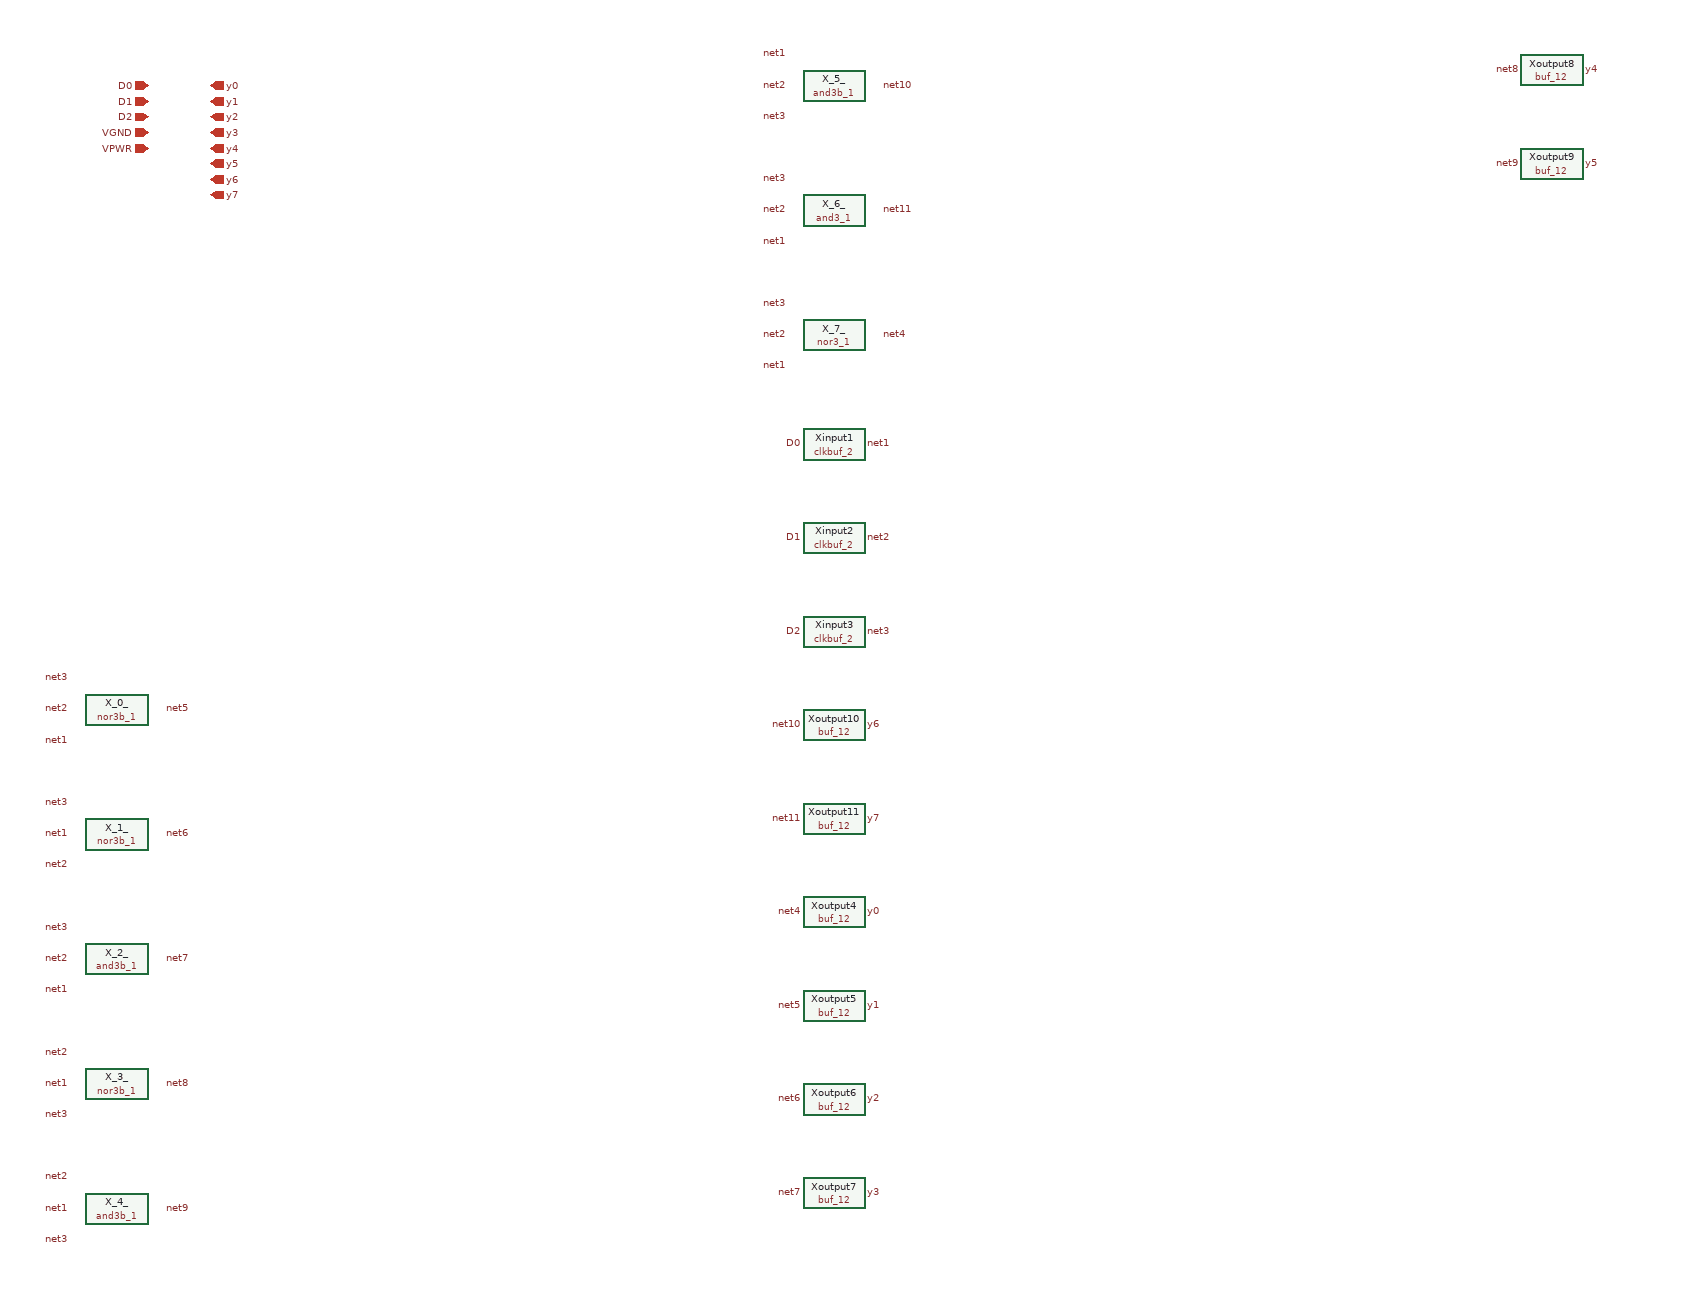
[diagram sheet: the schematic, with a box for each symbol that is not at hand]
v {xschem version=3.4.4 file_version=1.2
}
G {}
K {}
V {}
S {}
E {}
C {devices/ipin.sym} 190 20 0 0 {name=p54 lab=D0 }
C {devices/ipin.sym} 190 40 0 0 {name=p55 lab=D1 }
C {devices/ipin.sym} 190 60 0 0 {name=p56 lab=D2 }
C {devices/ipin.sym} 190 80 0 0 {name=p57 lab=VGND }
C {devices/ipin.sym} 190 100 0 0 {name=p58 lab=VPWR }
C {devices/opin.sym} 270 20 0 0 {name=p59 lab=y0 }
C {devices/opin.sym} 270 40 0 0 {name=p60 lab=y1 }
C {devices/opin.sym} 270 60 0 0 {name=p61 lab=y2 }
C {devices/opin.sym} 270 80 0 0 {name=p62 lab=y3 }
C {devices/opin.sym} 270 100 0 0 {name=p63 lab=y4 }
C {devices/opin.sym} 270 120 0 0 {name=p64 lab=y5 }
C {devices/opin.sym} 270 140 0 0 {name=p65 lab=y6 }
C {devices/opin.sym} 270 160 0 0 {name=p66 lab=y7 }
C {devices/lab_pin.sym} 90 780 0 0 {name=p0 lab=net3 }
C {devices/lab_pin.sym} 90 820 0 0 {name=p1 lab=net2 }
C {devices/lab_pin.sym} 90 860 0 0 {name=p2 lab=net1 }
C {devices/lab_pin.sym} 210 820 0 1 {name=p3 lab=net5 }
C {sky130_stdcells/nor3b_1.sym} 150 820 0 0 {name=X_0_ VGND=VGND VNB=VGND VPB=VPWR VPWR=VPWR }
C {devices/lab_pin.sym} 90 940 0 0 {name=p4 lab=net3 }
C {devices/lab_pin.sym} 90 980 0 0 {name=p5 lab=net1 }
C {devices/lab_pin.sym} 90 1020 0 0 {name=p6 lab=net2 }
C {devices/lab_pin.sym} 210 980 0 1 {name=p7 lab=net6 }
C {sky130_stdcells/nor3b_1.sym} 150 980 0 0 {name=X_1_ VGND=VGND VNB=VGND VPB=VPWR VPWR=VPWR }
C {devices/lab_pin.sym} 90 1100 0 0 {name=p8 lab=net3 }
C {devices/lab_pin.sym} 90 1140 0 0 {name=p9 lab=net2 }
C {devices/lab_pin.sym} 90 1180 0 0 {name=p10 lab=net1 }
C {devices/lab_pin.sym} 210 1140 0 1 {name=p11 lab=net7 }
C {sky130_stdcells/and3b_1.sym} 150 1140 0 0 {name=X_2_ VGND=VGND VNB=VGND VPB=VPWR VPWR=VPWR }
C {devices/lab_pin.sym} 90 1260 0 0 {name=p12 lab=net2 }
C {devices/lab_pin.sym} 90 1300 0 0 {name=p13 lab=net1 }
C {devices/lab_pin.sym} 90 1340 0 0 {name=p14 lab=net3 }
C {devices/lab_pin.sym} 210 1300 0 1 {name=p15 lab=net8 }
C {sky130_stdcells/nor3b_1.sym} 150 1300 0 0 {name=X_3_ VGND=VGND VNB=VGND VPB=VPWR VPWR=VPWR }
C {devices/lab_pin.sym} 90 1420 0 0 {name=p16 lab=net2 }
C {devices/lab_pin.sym} 90 1460 0 0 {name=p17 lab=net1 }
C {devices/lab_pin.sym} 90 1500 0 0 {name=p18 lab=net3 }
C {devices/lab_pin.sym} 210 1460 0 1 {name=p19 lab=net9 }
C {sky130_stdcells/and3b_1.sym} 150 1460 0 0 {name=X_4_ VGND=VGND VNB=VGND VPB=VPWR VPWR=VPWR }
C {devices/lab_pin.sym} 1010 -20 0 0 {name=p20 lab=net1 }
C {devices/lab_pin.sym} 1010 20 0 0 {name=p21 lab=net2 }
C {devices/lab_pin.sym} 1010 60 0 0 {name=p22 lab=net3 }
C {devices/lab_pin.sym} 1130 20 0 1 {name=p23 lab=net10 }
C {sky130_stdcells/and3b_1.sym} 1070 20 0 0 {name=X_5_ VGND=VGND VNB=VGND VPB=VPWR VPWR=VPWR }
C {devices/lab_pin.sym} 1010 140 0 0 {name=p24 lab=net3 }
C {devices/lab_pin.sym} 1010 180 0 0 {name=p25 lab=net2 }
C {devices/lab_pin.sym} 1010 220 0 0 {name=p26 lab=net1 }
C {devices/lab_pin.sym} 1130 180 0 1 {name=p27 lab=net11 }
C {sky130_stdcells/and3_1.sym} 1070 180 0 0 {name=X_6_ VGND=VGND VNB=VGND VPB=VPWR VPWR=VPWR }
C {devices/lab_pin.sym} 1010 300 0 0 {name=p28 lab=net3 }
C {devices/lab_pin.sym} 1010 340 0 0 {name=p29 lab=net2 }
C {devices/lab_pin.sym} 1010 380 0 0 {name=p30 lab=net1 }
C {devices/lab_pin.sym} 1130 340 0 1 {name=p31 lab=net4 }
C {sky130_stdcells/nor3_1.sym} 1070 340 0 0 {name=X_7_ VGND=VGND VNB=VGND VPB=VPWR VPWR=VPWR }
C {devices/lab_pin.sym} 1030 480 0 0 {name=p32 lab=D0 }
C {devices/lab_pin.sym} 1110 480 0 1 {name=p33 lab=net1 }
C {sky130_stdcells/clkbuf_2.sym} 1070 480 0 0 {name=Xinput1 VGND=VGND VNB=VGND VPB=VPWR VPWR=VPWR }
C {devices/lab_pin.sym} 1030 600 0 0 {name=p34 lab=D1 }
C {devices/lab_pin.sym} 1110 600 0 1 {name=p35 lab=net2 }
C {sky130_stdcells/clkbuf_2.sym} 1070 600 0 0 {name=Xinput2 VGND=VGND VNB=VGND VPB=VPWR VPWR=VPWR }
C {devices/lab_pin.sym} 1030 720 0 0 {name=p36 lab=D2 }
C {devices/lab_pin.sym} 1110 720 0 1 {name=p37 lab=net3 }
C {sky130_stdcells/clkbuf_2.sym} 1070 720 0 0 {name=Xinput3 VGND=VGND VNB=VGND VPB=VPWR VPWR=VPWR }
C {devices/lab_pin.sym} 1030 840 0 0 {name=p38 lab=net10 }
C {devices/lab_pin.sym} 1110 840 0 1 {name=p39 lab=y6 }
C {sky130_stdcells/buf_12.sym} 1070 840 0 0 {name=Xoutput10 VGND=VGND VNB=VGND VPB=VPWR VPWR=VPWR }
C {devices/lab_pin.sym} 1030 960 0 0 {name=p40 lab=net11 }
C {devices/lab_pin.sym} 1110 960 0 1 {name=p41 lab=y7 }
C {sky130_stdcells/buf_12.sym} 1070 960 0 0 {name=Xoutput11 VGND=VGND VNB=VGND VPB=VPWR VPWR=VPWR }
C {devices/lab_pin.sym} 1030 1080 0 0 {name=p42 lab=net4 }
C {devices/lab_pin.sym} 1110 1080 0 1 {name=p43 lab=y0 }
C {sky130_stdcells/buf_12.sym} 1070 1080 0 0 {name=Xoutput4 VGND=VGND VNB=VGND VPB=VPWR VPWR=VPWR }
C {devices/lab_pin.sym} 1030 1200 0 0 {name=p44 lab=net5 }
C {devices/lab_pin.sym} 1110 1200 0 1 {name=p45 lab=y1 }
C {sky130_stdcells/buf_12.sym} 1070 1200 0 0 {name=Xoutput5 VGND=VGND VNB=VGND VPB=VPWR VPWR=VPWR }
C {devices/lab_pin.sym} 1030 1320 0 0 {name=p46 lab=net6 }
C {devices/lab_pin.sym} 1110 1320 0 1 {name=p47 lab=y2 }
C {sky130_stdcells/buf_12.sym} 1070 1320 0 0 {name=Xoutput6 VGND=VGND VNB=VGND VPB=VPWR VPWR=VPWR }
C {devices/lab_pin.sym} 1030 1440 0 0 {name=p48 lab=net7 }
C {devices/lab_pin.sym} 1110 1440 0 1 {name=p49 lab=y3 }
C {sky130_stdcells/buf_12.sym} 1070 1440 0 0 {name=Xoutput7 VGND=VGND VNB=VGND VPB=VPWR VPWR=VPWR }
C {devices/lab_pin.sym} 1950 0 0 0 {name=p50 lab=net8 }
C {devices/lab_pin.sym} 2030 0 0 1 {name=p51 lab=y4 }
C {sky130_stdcells/buf_12.sym} 1990 0 0 0 {name=Xoutput8 VGND=VGND VNB=VGND VPB=VPWR VPWR=VPWR }
C {devices/lab_pin.sym} 1950 120 0 0 {name=p52 lab=net9 }
C {devices/lab_pin.sym} 2030 120 0 1 {name=p53 lab=y5 }
C {sky130_stdcells/buf_12.sym} 1990 120 0 0 {name=Xoutput9 VGND=VGND VNB=VGND VPB=VPWR VPWR=VPWR }
